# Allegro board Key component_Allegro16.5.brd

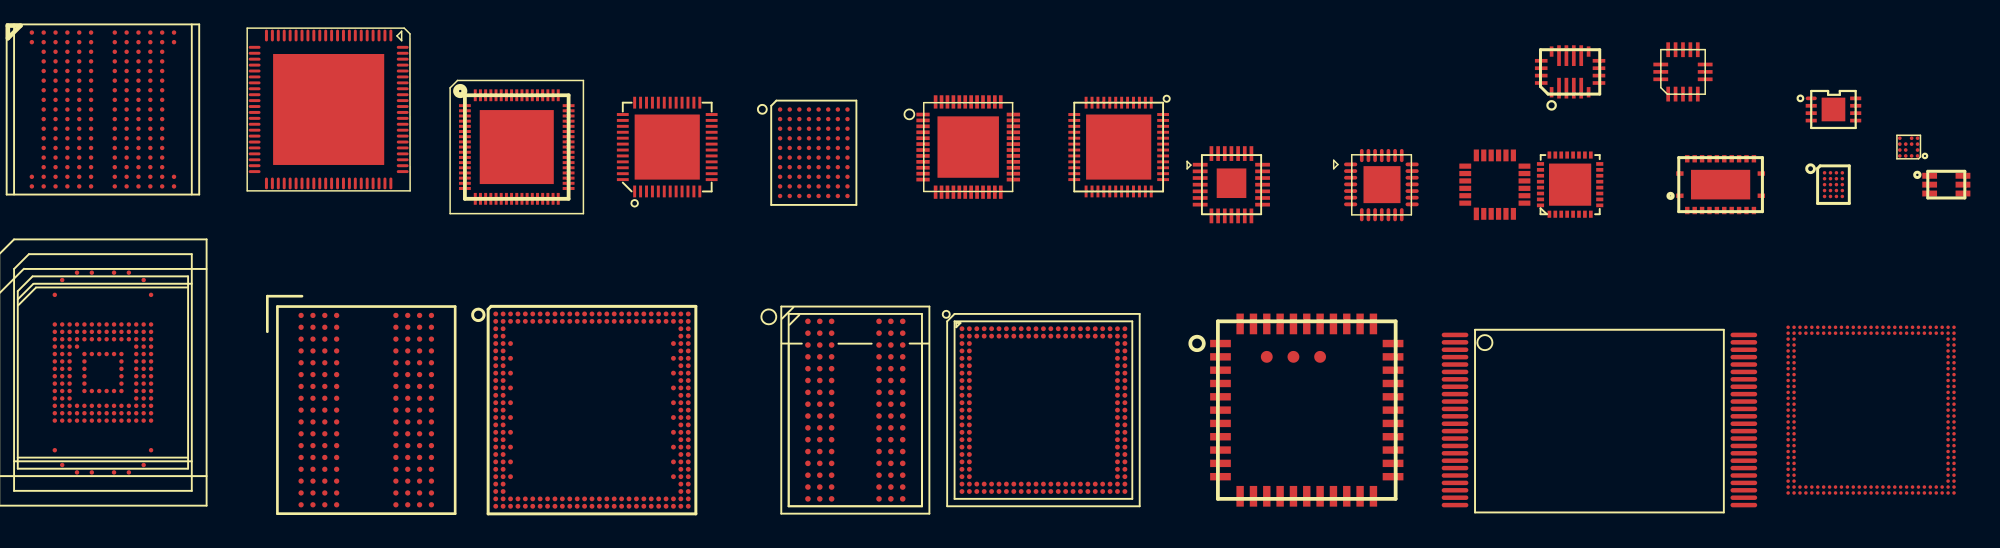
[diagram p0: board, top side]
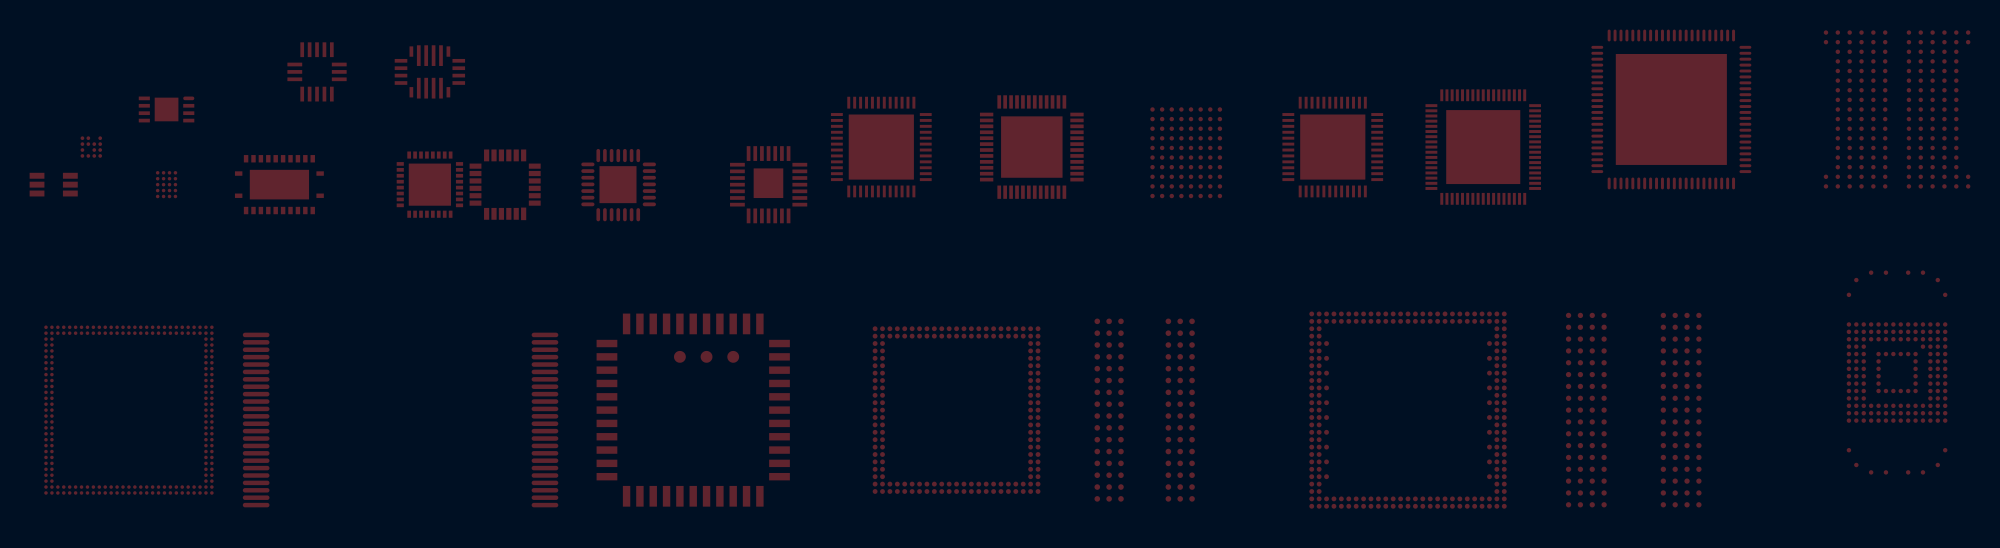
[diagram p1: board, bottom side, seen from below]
No outline. copper layers: TOP, BOTTOM. Coordinates in mm from the lowest, leftmost part position.

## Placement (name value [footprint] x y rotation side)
U1  -  [136BALL-FBGA]  17.78 0 0 top
U2  -  [763_ALC3224]  58.42 17.78 0 top
U3  -  [ALC5616_QFN32]  99.06 15.24 0 top
U4  -  [ALC5631Q]  68.58 17.78 0 top
U5  -  [AP6XXX]  81.28 0 0 top
U6  -  [BAG14-1_6X1_6]  121.92 17.78 0 top
U7  -  [CSP0608-80]  45.72 20.32 0 top
U8  -  [CW2013]  116.84 20.32 0 top
U9  -  [ES8323-]  86.36 15.24 0 top
U10  -  [B-168P_12-12]  63.5 0 0 top
U11  -  [FBGA178-13X11_5]  0 20.32 0 top
U12  -  [FBGA216-12X12]  119.38 0 0 top
U13  -  [FBGA220-14X14]  33.02 0 0 top
U14  -  [FBGA96-10X14]  50.8 0 0 top
U15  -  [INAND_169]  0 2.54 0 top
U16  -  [LGA16]  106.68 22.86 0 top
U17  -  [MPU6050C]  93.98 15.24 0 top
U18  -  [OPLGA6]  124.46 15.24 0 top
U19  -  [QFN20-3X4]  99.06 22.86 0 top
U20  -  [QFN48-6X6]  38.1 17.78 0 top
U21  -  [QFN68-7X7]  27.94 17.78 0 top
U22  -  [QFN88]  15.24 20.32 0 top
U23  -  [TSOP1-48]  91.44 5.08 0 top
U24  -  [VQFN24]  109.22 15.24 0 top
U25  -  [WLCSP-20]  116.84 15.24 0 top
U26  -  [WM8988]  76.2 15.24 0 top

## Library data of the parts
U1 = 136BALL-FBGA
U2 = 763_ALC3224
U3 = ALC5616_QFN32
U4 = ALC5631Q
U5 = AP6XXX
U6 = BAG14-1_6X1_6
U7 = CSP0608-80
U8 = CW2013
U9 = ES8323-
U10 = FBGA168-12X12
U11 = FBGA178-13X11_5
U12 = FBGA216-12X12
U13 = FBGA220-14X14
U14 = FBGA96-10X14
U15 = INAND_169
U16 = LGA16
U17 = MPU6050C
U18 = OPLGA6
U19 = QFN20-3X4
U20 = QFN48-6X6
U21 = QFN68-7X7
U22 = QFN88
U23 = TSOP1-48
U24 = VQFN24
U25 = WLCSP-20
U26 = WM8988

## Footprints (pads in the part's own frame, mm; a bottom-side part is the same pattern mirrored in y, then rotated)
136BALL-FBGA
  round 0.36 smd: A1(-4.4,6.4) A2(-3.6,6.4) A3(-2.8,6.4) A4(-2,6.4) A9(2,6.4) A10(2.8,6.4) A11(3.6,6.4) A12(4.4,6.4) B1(-4.4,5.6) B2(-3.6,5.6) B3(-2.8,5.6) B4(-2,5.6) B9(2,5.6) B10(2.8,5.6) B11(3.6,5.6) B12(4.4,5.6) C1(-4.4,4.8) C2(-3.6,4.8) C3(-2.8,4.8) C4(-2,4.8) C9(2,4.8) C10(2.8,4.8) C11(3.6,4.8) C12(4.4,4.8) D1(-4.4,4) D2(-3.6,4) D3(-2.8,4) D4(-2,4) D9(2,4) D10(2.8,4) D11(3.6,4) D12(4.4,4) E1(-4.4,3.2) E2(-3.6,3.2) E3(-2.8,3.2) E4(-2,3.2) E9(2,3.2) E10(2.8,3.2) E11(3.6,3.2) E12(4.4,3.2) F1(-4.4,2.4) F2(-3.6,2.4) F3(-2.8,2.4) F4(-2,2.4) F9(2,2.4) F10(2.8,2.4) F11(3.6,2.4) F12(4.4,2.4) G1(-4.4,1.6) G2(-3.6,1.6) G3(-2.8,1.6) G4(-2,1.6) G9(2,1.6) G10(2.8,1.6) G11(3.6,1.6) G12(4.4,1.6) H1(-4.4,0.8) H2(-3.6,0.8) H3(-2.8,0.8) H4(-2,0.8) H9(2,0.8) H10(2.8,0.8) H11(3.6,0.8) H12(4.4,0.8) J1(-4.4,0) J2(-3.6,0) J3(-2.8,0) J4(-2,0) J9(2,0) J10(2.8,0) J11(3.6,0) J12(4.4,0) K1(-4.4,-0.8) K2(-3.6,-0.8) K3(-2.8,-0.8) K4(-2,-0.8) K9(2,-0.8) K10(2.8,-0.8) K11(3.6,-0.8) K12(4.4,-0.8) L1(-4.4,-1.6) L2(-3.6,-1.6) L3(-2.8,-1.6) L4(-2,-1.6) L9(2,-1.6) L10(2.8,-1.6) L11(3.6,-1.6) L12(4.4,-1.6) M1(-4.4,-2.4) M2(-3.6,-2.4) M3(-2.8,-2.4) M4(-2,-2.4) M9(2,-2.4) M10(2.8,-2.4) M11(3.6,-2.4) M12(4.4,-2.4) N1(-4.4,-3.2) N2(-3.6,-3.2) N3(-2.8,-3.2) N4(-2,-3.2) N9(2,-3.2) N10(2.8,-3.2) N11(3.6,-3.2) N12(4.4,-3.2) P1(-4.4,-4) P2(-3.6,-4) P3(-2.8,-4) P4(-2,-4) P9(2,-4) P10(2.8,-4) P11(3.6,-4) P12(4.4,-4) R1(-4.4,-4.8) R2(-3.6,-4.8) R3(-2.8,-4.8) R4(-2,-4.8) R9(2,-4.8) R10(2.8,-4.8) R11(3.6,-4.8) R12(4.4,-4.8) T1(-4.4,-5.6) T2(-3.6,-5.6) T3(-2.8,-5.6) T4(-2,-5.6) T9(2,-5.6) T10(2.8,-5.6) T11(3.6,-5.6) T12(4.4,-5.6) U1(-4.4,-6.4) U2(-3.6,-6.4) U3(-2.8,-6.4) U4(-2,-6.4) U9(2,-6.4) U10(2.8,-6.4) U11(3.6,-6.4) U12(4.4,-6.4)
763_ALC3224
  rect 0.9x0.249 smd: 1(-3.05,2.2) 2(-3.05,1.8) 3(-3.05,1.4) 4(-3.05,1) 5(-3.05,0.6) 6(-3.05,0.2) 7(-3.05,-0.2) 8(-3.05,-0.6) 9(-3.05,-1) 10(-3.05,-1.4) 11(-3.05,-1.8) 12(-3.05,-2.2) 25(3.05,-2.2) 26(3.05,-1.8) 27(3.05,-1.4) 28(3.05,-1) 29(3.05,-0.6) 30(3.05,-0.2) 31(3.05,0.2) 32(3.05,0.6) 33(3.05,1) 34(3.05,1.4) 35(3.05,1.8) 36(3.05,2.2)
  rect 0.249x0.9 smd: 13(-2.2,-3.05) 14(-1.8,-3.05) 15(-1.4,-3.05) 16(-1,-3.05) 17(-0.6,-3.05) 18(-0.2,-3.05) 19(0.2,-3.05) 20(0.6,-3.05) 21(1,-3.05) 22(1.4,-3.05) 23(1.8,-3.05) 24(2.2,-3.05) 37(2.2,3.05) 38(1.8,3.05) 39(1.4,3.05) 40(1,3.05) 41(0.6,3.05) 42(0.2,3.05) 43(-0.2,3.05) 44(-0.6,3.05) 45(-1,3.05) 46(-1.4,3.05) 47(-1.8,3.05) 48(-2.2,3.05)
  rect 4.15x4.15 smd: 49(0,0)
ALC5616_QFN32
  rect 0.25x0.482 smd: 1(-1.4,-2) 2(-1,-2) 3(-0.6,-2) 4(-0.2,-2) 5(0.2,-2) 6(0.6,-2) 7(1,-2) 8(1.4,-2) 17(1.4,2) 18(1,2) 19(0.6,2) 20(0.2,2) 21(-0.2,2) 22(-0.6,2) 23(-1,2) 24(-1.4,2)
  rect 0.482x0.25 smd: 9(2,-1.4) 10(2,-1) 11(2,-0.6) 12(2,-0.2) 13(2,0.2) 14(2,0.6) 15(2,1) 16(2,1.4) 25(-2,1.4) 26(-2,1) 27(-2,0.6) 28(-2,0.2) 29(-2,-0.2) 30(-2,-0.6) 31(-2,-1) 32(-2,-1.4)
  rect 2.85x2.85 smd: 33(0,0)
ALC5631Q
  rect 0.2x0.8 smd: 1(2.2,3) 2(1.8,3) 3(1.4,3) 4(1,3) 5(0.6,3) 6(0.2,3) 7(-0.2,3) 8(-0.6,3) 9(-1,3) 10(-1.4,3) 11(-1.8,3) 12(-2.2,3) 25(-2.2,-3) 26(-1.8,-3) 27(-1.4,-3) 28(-1,-3) 29(-0.6,-3) 30(-0.2,-3) 31(0.2,-3) 32(0.6,-3) 33(1,-3) 34(1.4,-3) 35(1.8,-3) 36(2.2,-3)
  rect 0.8x0.2 smd: 13(-3,2.2) 14(-3,1.8) 15(-3,1.4) 16(-3,1) 17(-3,0.6) 18(-3,0.2) 19(-3,-0.2) 20(-3,-0.6) 21(-3,-1) 22(-3,-1.4) 23(-3,-1.8) 24(-3,-2.2) 37(3,-2.2) 38(3,-1.8) 39(3,-1.4) 40(3,-1) 41(3,-0.6) 42(3,-0.2) 43(3,0.2) 44(3,0.6) 45(3,1) 46(3,1.4) 47(3,1.8) 48(3,2.2)
  rect 4.4x4.4 smd: 49(0,0)
AP6XXX
  rect 1.4x0.5 smd: 1(-5.825,4.5) 2(-5.825,3.6) 3(-5.825,2.7) 4(-5.825,1.8) 5(-5.825,0.9) 6(-5.825,0) 7(-5.825,-0.9) 8(-5.825,-1.8) 9(-5.825,-2.7) 10(-5.825,-3.6) 11(-5.825,-4.5) 23(5.825,-4.5) 24(5.825,-3.6) 25(5.825,-2.7) 26(5.825,-1.8) 27(5.825,-0.9) 28(5.825,0) 29(5.825,0.9) 30(5.825,1.8) 31(5.825,2.7) 32(5.825,3.6) 33(5.825,4.5)
  rect 0.5x1.4 smd: 12(-4.5,-5.825) 13(-3.6,-5.825) 14(-2.7,-5.825) 15(-1.8,-5.825) 16(-0.9,-5.825) 17(0,-5.825) 18(0.9,-5.825) 19(1.8,-5.825) 20(2.7,-5.825) 21(3.6,-5.825) 22(4.5,-5.825) 34(4.5,5.825) 35(3.6,5.825) 36(2.7,5.825) 37(1.8,5.825) 38(0.9,5.825) 39(0,5.825) 40(-0.9,5.825) 41(-1.8,5.825) 42(-2.7,5.825) 43(-3.6,5.825) 44(-4.5,5.825)
  round 0.8 smd: 45(-2.7,3.6) 46(-0.9,3.6) 47(0.9,3.6)
B-168P_12-12
  round 0.33 smd: A1(-5.5,5.5) A2(-5,5.5) A3(-4.5,5.5) A4(-4,5.5) A5(-3.5,5.5) A6(-3,5.5) A7(-2.5,5.5) A8(-2,5.5) A9(-1.5,5.5) A10(-1,5.5) A11(-0.5,5.5) A12(0,5.5) A13(0.5,5.5) A14(1,5.5) A15(1.5,5.5) A16(2,5.5) A17(2.5,5.5) A18(3,5.5) A19(3.5,5.5) A20(4,5.5) A21(4.5,5.5) A22(5,5.5) A23(5.5,5.5) AA1(-5.5,-4.5) AA2(-5,-4.5) AA22(5,-4.5) AA23(5.5,-4.5) AB1(-5.5,-5) AB2(-5,-5) AB3(-4.5,-5) AB4(-4,-5) AB5(-3.5,-5) AB6(-3,-5) AB7(-2.5,-5) AB8(-2,-5) AB9(-1.5,-5) AB10(-1,-5) AB11(-0.5,-5) AB12(0,-5) AB13(0.5,-5) AB14(1,-5) AB15(1.5,-5) AB16(2,-5) AB17(2.5,-5) AB18(3,-5) AB19(3.5,-5) AB20(4,-5) AB21(4.5,-5) AB22(5,-5) AB23(5.5,-5) AC1(-5.5,-5.5) AC2(-5,-5.5) AC3(-4.5,-5.5) AC4(-4,-5.5) AC5(-3.5,-5.5) AC6(-3,-5.5) AC7(-2.5,-5.5) AC8(-2,-5.5) AC9(-1.5,-5.5) AC10(-1,-5.5) AC11(-0.5,-5.5) AC12(0,-5.5) AC13(0.5,-5.5) AC14(1,-5.5) AC15(1.5,-5.5) AC16(2,-5.5) AC17(2.5,-5.5) AC18(3,-5.5) AC19(3.5,-5.5) AC20(4,-5.5) AC21(4.5,-5.5) AC22(5,-5.5) AC23(5.5,-5.5) B1(-5.5,5) B2(-5,5) B3(-4.5,5) B4(-4,5) B5(-3.5,5) B6(-3,5) B7(-2.5,5) B8(-2,5) B9(-1.5,5) B10(-1,5) B11(-0.5,5) B12(0,5) B13(0.5,5) B14(1,5) B15(1.5,5) B16(2,5) B17(2.5,5) B18(3,5) B19(3.5,5) B20(4,5) B21(4.5,5) B22(5,5) B23(5.5,5) C1(-5.5,4.5) C2(-5,4.5) C22(5,4.5) C23(5.5,4.5) D1(-5.5,4) D2(-5,4) D22(5,4) D23(5.5,4) E1(-5.5,3.5) E2(-5,3.5) E22(5,3.5) E23(5.5,3.5) F1(-5.5,3) F2(-5,3) F22(5,3) F23(5.5,3) G1(-5.5,2.5) G2(-5,2.5) G22(5,2.5) G23(5.5,2.5) H1(-5.5,2) H2(-5,2) H22(5,2) H23(5.5,2) J1(-5.5,1.5) J2(-5,1.5) J22(5,1.5) J23(5.5,1.5) K1(-5.5,1) K2(-5,1) K22(5,1) K23(5.5,1) L1(-5.5,0.5) L2(-5,0.5) L22(5,0.5) L23(5.5,0.5) M1(-5.5,0) M2(-5,0) M22(5,0) M23(5.5,0) N1(-5.5,-0.5) N2(-5,-0.5) N22(5,-0.5) N23(5.5,-0.5) P1(-5.5,-1) P2(-5,-1) P22(5,-1) P23(5.5,-1) R1(-5.5,-1.5) R2(-5,-1.5) R22(5,-1.5) R23(5.5,-1.5) T1(-5.5,-2) T2(-5,-2) T22(5,-2) T23(5.5,-2) U1(-5.5,-2.5) U2(-5,-2.5) U22(5,-2.5) U23(5.5,-2.5) V1(-5.5,-3) V2(-5,-3) V22(5,-3) V23(5.5,-3) W1(-5.5,-3.5) W2(-5,-3.5) W22(5,-3.5) W23(5.5,-3.5) Y1(-5.5,-4) Y2(-5,-4) Y22(5,-4) Y23(5.5,-4)
BAG14-1_6X1_6
  round 0.25 smd: A1(0.6,-0.6) A2(0.2,-0.6) A3(-0.2,-0.6) A4(-0.6,-0.6) B1(0.6,-0.2) B3(-0.2,-0.2) B4(-0.6,-0.2) C1(0.6,0.2) C2(0.2,0.2) C3(-0.2,0.2) C4(-0.6,0.2) D1(0.6,0.6) D2(0.2,0.6) D4(-0.6,0.6)
CSP0608-80
  round 0.3 smd: A1(0,0) A2(0.65,0) A3(1.3,0) A4(1.95,0) A5(2.6,0) A6(3.25,0) A7(3.9,0) A8(4.55,0) B1(0,-0.65) B2(0.65,-0.65) B3(1.3,-0.65) B4(1.95,-0.65) B5(2.6,-0.65) B6(3.25,-0.65) B7(3.9,-0.65) B8(4.55,-0.65) C1(0,-1.3) C2(0.65,-1.3) C3(1.3,-1.3) C4(1.95,-1.3) C5(2.6,-1.3) C6(3.25,-1.3) C7(3.9,-1.3) C8(4.55,-1.3) D1(0,-1.95) D2(0.65,-1.95) D3(1.3,-1.95) D4(1.95,-1.95) D5(2.6,-1.95) D6(3.25,-1.95) D7(3.9,-1.95) D8(4.55,-1.95) E1(0,-2.6) E2(0.65,-2.6) E3(1.3,-2.6) E4(1.95,-2.6) E5(2.6,-2.6) E6(3.25,-2.6) E7(3.9,-2.6) E8(4.55,-2.6) F1(0,-3.25) F2(0.65,-3.25) F3(1.3,-3.25) F4(1.95,-3.25) F5(2.6,-3.25) F6(3.25,-3.25) F7(3.9,-3.25) F8(4.55,-3.25) G1(0,-3.9) G2(0.65,-3.9) G3(1.3,-3.9) G4(1.95,-3.9) G5(2.6,-3.9) G6(3.25,-3.9) G7(3.9,-3.9) G8(4.55,-3.9) H1(0,-4.55) H2(0.65,-4.55) H3(1.3,-4.55) H4(1.95,-4.55) H5(2.6,-4.55) H6(3.25,-4.55) H7(3.9,-4.55) H8(4.55,-4.55) J1(0,-5.2) J2(0.65,-5.2) J3(1.3,-5.2) J4(1.95,-5.2) J5(2.6,-5.2) J6(3.25,-5.2) J7(3.9,-5.2) J8(4.55,-5.2) K1(0,-5.85) K2(0.65,-5.85) K3(1.3,-5.85) K4(1.95,-5.85) K5(2.6,-5.85) K6(3.25,-5.85) K7(3.9,-5.85) K8(4.55,-5.85)
CW2013
  oval 0.75x0.25 smd: 1(-1.5,0.75)
  rect 0.75x0.25 smd: 2(-1.5,0.25) 3(-1.5,-0.25) 4(-1.5,-0.75) 5(1.5,-0.75) 6(1.5,-0.25) 7(1.5,0.25) 8(1.5,0.75)
  rect 1.6x1.6 smd: 9(0,0)
ES8323-
  oval 0.889x0.254 smd: 1(-2.118,1.367) 2(-2.118,0.917) 3(-2.118,0.467) 4(-2.118,0.017) 5(-2.118,-0.433) 6(-2.118,-0.883) 7(-2.118,-1.333) 15(2.032,-1.333) 16(2.032,-0.883) 17(2.032,-0.433) 18(2.032,0.017) 19(2.032,0.467) 20(2.032,0.917) 21(2.032,1.367)
  oval 0.245x0.889 smd: 8(-1.368,-2.033) 9(-0.918,-2.033) 10(-0.468,-2.033) 11(-0.018,-2.033) 12(0.432,-2.033) 13(0.882,-2.033) 14(1.332,-2.033) 22(1.332,1.967) 23(0.882,1.967) 24(0.432,1.967) 25(-0.018,1.967) 26(-0.468,1.967) 27(-0.918,1.967) 28(-1.368,1.967)
  rect 2.5x2.5 smd: 29(0,0)
FBGA96-10X14
  round 0.38 smd: A1(-3.2,6) A2(-2.4,6) A3(-1.6,6) A7(1.6,6) A8(2.4,6) A9(3.2,6) B1(-3.2,5.2) B2(-2.4,5.2) B3(-1.6,5.2) B7(1.6,5.2) B8(2.4,5.2) B9(3.2,5.2) C1(-3.2,4.4) C2(-2.4,4.4) C3(-1.6,4.4) C7(1.6,4.4) C8(2.4,4.4) C9(3.2,4.4) D1(-3.2,3.6) D2(-2.4,3.6) D3(-1.6,3.6) D7(1.6,3.6) D8(2.4,3.6) D9(3.2,3.6) E1(-3.2,2.8) E2(-2.4,2.8) E3(-1.6,2.8) E7(1.6,2.8) E8(2.4,2.8) E9(3.2,2.8) F1(-3.2,2) F2(-2.4,2) F3(-1.6,2) F7(1.6,2) F8(2.4,2) F9(3.2,2) G1(-3.2,1.2) G2(-2.4,1.2) G3(-1.6,1.2) G7(1.6,1.2) G8(2.4,1.2) G9(3.2,1.2) H1(-3.2,0.4) H2(-2.4,0.4) H3(-1.6,0.4) H7(1.6,0.4) H8(2.4,0.4) H9(3.2,0.4) J1(-3.2,-0.4) J2(-2.4,-0.4) J3(-1.6,-0.4) J7(1.6,-0.4) J8(2.4,-0.4) J9(3.2,-0.4) K1(-3.2,-1.2) K2(-2.4,-1.2) K3(-1.6,-1.2) K7(1.6,-1.2) K8(2.4,-1.2) K9(3.2,-1.2) L1(-3.2,-2) L2(-2.4,-2) L3(-1.6,-2) L7(1.6,-2) L8(2.4,-2) L9(3.2,-2) M1(-3.2,-2.8) M2(-2.4,-2.8) M3(-1.6,-2.8) M7(1.6,-2.8) M8(2.4,-2.8) M9(3.2,-2.8) N1(-3.2,-3.6) N2(-2.4,-3.6) N3(-1.6,-3.6) N7(1.6,-3.6) N8(2.4,-3.6) N9(3.2,-3.6) P1(-3.2,-4.4) P2(-2.4,-4.4) P3(-1.6,-4.4) P7(1.6,-4.4) P8(2.4,-4.4) P9(3.2,-4.4) R1(-3.2,-5.2) R2(-2.4,-5.2) R3(-1.6,-5.2) R7(1.6,-5.2) R8(2.4,-5.2) R9(3.2,-5.2) T1(-3.2,-6) T2(-2.4,-6) T3(-1.6,-6) T7(1.6,-6) T8(2.4,-6) T9(3.2,-6)
FBGA178-13X11_5
  round 0.3 smd: A1(-4.8,5.2) A2(-4,5.2) A3(-3.2,5.2) A4(-2.4,5.2) A5(-1.6,5.2) A6(-0.8,5.2) A8(0.8,5.2) A9(1.6,5.2) A10(2.4,5.2) A11(3.2,5.2) A12(4,5.2) A13(4.8,5.2) B1(-4.8,4.55) B2(-4,4.55) B3(-3.2,4.55) B4(-2.4,4.55) B5(-1.6,4.55) B6(-0.8,4.55) B8(0.8,4.55) B9(1.6,4.55) B10(2.4,4.55) B11(3.2,4.55) B12(4,4.55) B13(4.8,4.55) C2(-4,3.9) C3(-3.2,3.9) C4(-2.4,3.9) C5(-1.6,3.9) C6(-0.8,3.9) C8(0.8,3.9) C9(1.6,3.9) C10(2.4,3.9) C11(3.2,3.9) C12(4,3.9) D2(-4,3.25) D3(-3.2,3.25) D4(-2.4,3.25) D5(-1.6,3.25) D6(-0.8,3.25) D8(0.8,3.25) D9(1.6,3.25) D10(2.4,3.25) D11(3.2,3.25) D12(4,3.25) E2(-4,2.6) E3(-3.2,2.6) E4(-2.4,2.6) E5(-1.6,2.6) E6(-0.8,2.6) E8(0.8,2.6) E9(1.6,2.6) E10(2.4,2.6) E11(3.2,2.6) E12(4,2.6) F2(-4,1.95) F3(-3.2,1.95) F4(-2.4,1.95) F5(-1.6,1.95) F6(-0.8,1.95) F8(0.8,1.95) F9(1.6,1.95) F10(2.4,1.95) F11(3.2,1.95) F12(4,1.95) G2(-4,1.3) G3(-3.2,1.3) G4(-2.4,1.3) G5(-1.6,1.3) G6(-0.8,1.3) G8(0.8,1.3) G9(1.6,1.3) G10(2.4,1.3) G11(3.2,1.3) G12(4,1.3) H2(-4,0.65) H3(-3.2,0.65) H4(-2.4,0.65) H5(-1.6,0.65) H6(-0.8,0.65) H8(0.8,0.65) H9(1.6,0.65) H10(2.4,0.65) H11(3.2,0.65) H12(4,0.65) J2(-4,0) J3(-3.2,0) J4(-2.4,0) J5(-1.6,0) J6(-0.8,0) J8(0.8,0) J9(1.6,0) J10(2.4,0) J11(3.2,0) J12(4,0) K2(-4,-0.65) K3(-3.2,-0.65) K4(-2.4,-0.65) K5(-1.6,-0.65) K6(-0.8,-0.65) K8(0.8,-0.65) K9(1.6,-0.65) K10(2.4,-0.65) K11(3.2,-0.65) K12(4,-0.65) L2(-4,-1.3) L3(-3.2,-1.3) L4(-2.4,-1.3) L5(-1.6,-1.3) L6(-0.8,-1.3) L8(0.8,-1.3) L9(1.6,-1.3) L10(2.4,-1.3) L11(3.2,-1.3) L12(4,-1.3) M2(-4,-1.95) M3(-3.2,-1.95) M4(-2.4,-1.95) M5(-1.6,-1.95) M6(-0.8,-1.95) M8(0.8,-1.95) M9(1.6,-1.95) M10(2.4,-1.95) M11(3.2,-1.95) M12(4,-1.95) N2(-4,-2.6) N3(-3.2,-2.6) N4(-2.4,-2.6) N5(-1.6,-2.6) N6(-0.8,-2.6) N8(0.8,-2.6) N9(1.6,-2.6) N10(2.4,-2.6) N11(3.2,-2.6) N12(4,-2.6) P2(-4,-3.25) P3(-3.2,-3.25) P4(-2.4,-3.25) P5(-1.6,-3.25) P6(-0.8,-3.25) P8(0.8,-3.25) P9(1.6,-3.25) P10(2.4,-3.25) P11(3.2,-3.25) P12(4,-3.25) R2(-4,-3.9) R3(-3.2,-3.9) R4(-2.4,-3.9) R5(-1.6,-3.9) R6(-0.8,-3.9) R8(0.8,-3.9) R9(1.6,-3.9) R10(2.4,-3.9) R11(3.2,-3.9) R12(4,-3.9) T1(-4.8,-4.55) T2(-4,-4.55) T3(-3.2,-4.55) T4(-2.4,-4.55) T5(-1.6,-4.55) T6(-0.8,-4.55) T8(0.8,-4.55) T9(1.6,-4.55) T10(2.4,-4.55) T11(3.2,-4.55) T12(4,-4.55) T13(4.8,-4.55) U1(-4.8,-5.2) U2(-4,-5.2) U3(-3.2,-5.2) U4(-2.4,-5.2) U5(-1.6,-5.2) U6(-0.8,-5.2) U8(0.8,-5.2) U9(1.6,-5.2) U10(2.4,-5.2) U11(3.2,-5.2) U12(4,-5.2) U13(4.8,-5.2)
FBGA216-12X12
  round 0.24 smd: A1(-5.6,5.6) A2(-5.2,5.6) A3(-4.8,5.6) A4(-4.4,5.6) A5(-4,5.6) A6(-3.6,5.6) A7(-3.2,5.6) A8(-2.8,5.6) A9(-2.4,5.6) A10(-2,5.6) A11(-1.6,5.6) A12(-1.2,5.6) A13(-0.8,5.6) A14(-0.4,5.6) A15(0,5.6) A16(0.4,5.6) A17(0.8,5.6) A18(1.2,5.6) A19(1.6,5.6) A20(2,5.6) A21(2.4,5.6) A22(2.8,5.6) A23(3.2,5.6) A24(3.6,5.6) A25(4,5.6) A26(4.4,5.6) A27(4.8,5.6) A28(5.2,5.6) A29(5.6,5.6) AA1(-5.6,-2.4) AA2(-5.2,-2.4) AA28(5.2,-2.4) AA29(5.6,-2.4) AB1(-5.6,-2.8) AB2(-5.2,-2.8) AB28(5.2,-2.8) AB29(5.6,-2.8) AC1(-5.6,-3.2) AC2(-5.2,-3.2) AC28(5.2,-3.2) AC29(5.6,-3.2) AD1(-5.6,-3.6) AD2(-5.2,-3.6) AD28(5.2,-3.6) AD29(5.6,-3.6) AE1(-5.6,-4) AE2(-5.2,-4) AE28(5.2,-4) AE29(5.6,-4) AF1(-5.6,-4.4) AF2(-5.2,-4.4) AF28(5.2,-4.4) AF29(5.6,-4.4) AG1(-5.6,-4.8) AG2(-5.2,-4.8) AG28(5.2,-4.8) AG29(5.6,-4.8) AH1(-5.6,-5.2) AH2(-5.2,-5.2) AH3(-4.8,-5.2) AH4(-4.4,-5.2) AH5(-4,-5.2) AH6(-3.6,-5.2) AH7(-3.2,-5.2) AH8(-2.8,-5.2) AH9(-2.4,-5.2) AH10(-2,-5.2) AH11(-1.6,-5.2) AH12(-1.2,-5.2) AH13(-0.8,-5.2) AH14(-0.4,-5.2) AH15(0,-5.2) AH16(0.4,-5.2) AH17(0.8,-5.2) AH18(1.2,-5.2) AH19(1.6,-5.2) AH20(2,-5.2) AH21(2.4,-5.2) AH22(2.8,-5.2) AH23(3.2,-5.2) AH24(3.6,-5.2) AH25(4,-5.2) AH26(4.4,-5.2) AH27(4.8,-5.2) AH28(5.2,-5.2) AH29(5.6,-5.2) AJ1(-5.6,-5.6) AJ2(-5.2,-5.6) AJ3(-4.8,-5.6) AJ4(-4.4,-5.6) AJ5(-4,-5.6) AJ6(-3.6,-5.6) AJ7(-3.2,-5.6) AJ8(-2.8,-5.6) AJ9(-2.4,-5.6) AJ10(-2,-5.6) AJ11(-1.6,-5.6) AJ12(-1.2,-5.6) AJ13(-0.8,-5.6) AJ14(-0.4,-5.6) AJ15(0,-5.6) AJ16(0.4,-5.6) AJ17(0.8,-5.6) AJ18(1.2,-5.6) AJ19(1.6,-5.6) AJ20(2,-5.6) AJ21(2.4,-5.6) AJ22(2.8,-5.6) AJ23(3.2,-5.6) AJ24(3.6,-5.6) AJ25(4,-5.6) AJ26(4.4,-5.6) AJ27(4.8,-5.6) AJ28(5.2,-5.6) AJ29(5.6,-5.6) B1(-5.6,5.2) B2(-5.2,5.2) B3(-4.8,5.2) B4(-4.4,5.2) B5(-4,5.2) B6(-3.6,5.2) B7(-3.2,5.2) B8(-2.8,5.2) B9(-2.4,5.2) B10(-2,5.2) B11(-1.6,5.2) B12(-1.2,5.2) B13(-0.8,5.2) B14(-0.4,5.2) B15(0,5.2) B16(0.4,5.2) B17(0.8,5.2) B18(1.2,5.2) B19(1.6,5.2) B20(2,5.2) B21(2.4,5.2) B22(2.8,5.2) B23(3.2,5.2) B24(3.6,5.2) B25(4,5.2) B26(4.4,5.2) B27(4.8,5.2) B28(5.2,5.2) B29(5.6,5.2) C1(-5.6,4.8) C2(-5.2,4.8) C28(5.2,4.8) C29(5.6,4.8) D1(-5.6,4.4) D2(-5.2,4.4) D28(5.2,4.4) D29(5.6,4.4) E1(-5.6,4) E2(-5.2,4) E28(5.2,4) E29(5.6,4) F1(-5.6,3.6) F2(-5.2,3.6) F28(5.2,3.6) F29(5.6,3.6) G1(-5.6,3.2) G2(-5.2,3.2) G28(5.2,3.2) G29(5.6,3.2) H1(-5.6,2.8) H2(-5.2,2.8) H28(5.2,2.8) H29(5.6,2.8) J1(-5.6,2.4) J2(-5.2,2.4) J28(5.2,2.4) J29(5.6,2.4) K1(-5.6,2) K2(-5.2,2) K28(5.2,2) K29(5.6,2) L1(-5.6,1.6) L2(-5.2,1.6) L28(5.2,1.6) L29(5.6,1.6) M1(-5.6,1.2) M2(-5.2,1.2) M28(5.2,1.2) M29(5.6,1.2) N1(-5.6,0.8) N2(-5.2,0.8) N28(5.2,0.8) N29(5.6,0.8) P1(-5.6,0.4) P2(-5.2,0.4) P28(5.2,0.4) P29(5.6,0.4) R1(-5.6,0) R2(-5.2,0) R28(5.2,0) R29(5.6,0) T1(-5.6,-0.4) T2(-5.2,-0.4) T28(5.2,-0.4) T29(5.6,-0.4) U1(-5.6,-0.8) U2(-5.2,-0.8) U28(5.2,-0.8) U29(5.6,-0.8) V1(-5.6,-1.2) V2(-5.2,-1.2) V28(5.2,-1.2) V29(5.6,-1.2) W1(-5.6,-1.6) W2(-5.2,-1.6) W28(5.2,-1.6) W29(5.6,-1.6) Y1(-5.6,-2) Y2(-5.2,-2) Y28(5.2,-2) Y29(5.6,-2)
FBGA220-14X14
  round 0.33 smd: A1(-6.5,6.5) A2(-6,6.5) A3(-5.5,6.5) A4(-5,6.5) A5(-4.5,6.5) A6(-4,6.5) A7(-3.5,6.5) A8(-3,6.5) A9(-2.5,6.5) A10(-2,6.5) A11(-1.5,6.5) A12(-1,6.5) A13(-0.5,6.5) A14(0,6.5) A15(0.5,6.5) A16(1,6.5) A17(1.5,6.5) A18(2,6.5) A19(2.5,6.5) A20(3,6.5) A21(3.5,6.5) A22(4,6.5) A23(4.5,6.5) A24(5,6.5) A25(5.5,6.5) A26(6,6.5) A27(6.5,6.5) AA1(-6.5,-3.5) AA2(-6,-3.5) AA3(-5.5,-3.5) AA25(5.5,-3.5) AA26(6,-3.5) AA27(6.5,-3.5) AB1(-6.5,-4) AB2(-6,-4) AB26(6,-4) AB27(6.5,-4) AC1(-6.5,-4.5) AC2(-6,-4.5) AC3(-5.5,-4.5) AC25(5.5,-4.5) AC26(6,-4.5) AC27(6.5,-4.5) AD1(-6.5,-5) AD2(-6,-5) AD26(6,-5) AD27(6.5,-5) AE1(-6.5,-5.5) AE2(-6,-5.5) AE26(6,-5.5) AE27(6.5,-5.5) AF1(-6.5,-6) AF2(-6,-6) AF3(-5.5,-6) AF4(-5,-6) AF5(-4.5,-6) AF6(-4,-6) AF7(-3.5,-6) AF8(-3,-6) AF9(-2.5,-6) AF10(-2,-6) AF11(-1.5,-6) AF12(-1,-6) AF13(-0.5,-6) AF14(0,-6) AF15(0.5,-6) AF16(1,-6) AF17(1.5,-6) AF18(2,-6) AF19(2.5,-6) AF20(3,-6) AF21(3.5,-6) AF22(4,-6) AF23(4.5,-6) AF24(5,-6) AF25(5.5,-6) AF26(6,-6) AF27(6.5,-6) AG1(-6.5,-6.5) AG2(-6,-6.5) AG3(-5.5,-6.5) AG4(-5,-6.5) AG5(-4.5,-6.5) AG6(-4,-6.5) AG7(-3.5,-6.5) AG8(-3,-6.5) AG9(-2.5,-6.5) AG10(-2,-6.5) AG11(-1.5,-6.5) AG12(-1,-6.5) AG13(-0.5,-6.5) AG14(0,-6.5) AG15(0.5,-6.5) AG16(1,-6.5) AG17(1.5,-6.5) AG18(2,-6.5) AG19(2.5,-6.5) AG20(3,-6.5) AG21(3.5,-6.5) AG22(4,-6.5) AG23(4.5,-6.5) AG24(5,-6.5) AG25(5.5,-6.5) AG26(6,-6.5) AG27(6.5,-6.5) B1(-6.5,6) B2(-6,6) B3(-5.5,6) B4(-5,6) B5(-4.5,6) B6(-4,6) B7(-3.5,6) B8(-3,6) B9(-2.5,6) B10(-2,6) B11(-1.5,6) B12(-1,6) B13(-0.5,6) B14(0,6) B15(0.5,6) B16(1,6) B17(1.5,6) B18(2,6) B19(2.5,6) B20(3,6) B21(3.5,6) B22(4,6) B23(4.5,6) B24(5,6) B25(5.5,6) B26(6,6) B27(6.5,6) C1(-6.5,5.5) C2(-6,5.5) C26(6,5.5) C27(6.5,5.5) D1(-6.5,5) D2(-6,5) D26(6,5) D27(6.5,5) E1(-6.5,4.5) E2(-6,4.5) E3(-5.5,4.5) E25(5.5,4.5) E26(6,4.5) E27(6.5,4.5) F1(-6.5,4) F2(-6,4) F26(6,4) F27(6.5,4) G1(-6.5,3.5) G2(-6,3.5) G3(-5.5,3.5) G25(5.5,3.5) G26(6,3.5) G27(6.5,3.5) H1(-6.5,3) H2(-6,3) H26(6,3) H27(6.5,3) J1(-6.5,2.5) J2(-6,2.5) J3(-5.5,2.5) J25(5.5,2.5) J26(6,2.5) J27(6.5,2.5) K1(-6.5,2) K2(-6,2) K26(6,2) K27(6.5,2) L1(-6.5,1.5) L2(-6,1.5) L3(-5.5,1.5) L25(5.5,1.5) L26(6,1.5) L27(6.5,1.5) M1(-6.5,1) M2(-6,1) M26(6,1) M27(6.5,1) N1(-6.5,0.5) N2(-6,0.5) N3(-5.5,0.5) N25(5.5,0.5) N26(6,0.5) N27(6.5,0.5) P1(-6.5,0) P2(-6,0) P26(6,0) P27(6.5,0) R1(-6.5,-0.5) R2(-6,-0.5) R3(-5.5,-0.5) R25(5.5,-0.5) R26(6,-0.5) R27(6.5,-0.5) T1(-6.5,-1) T2(-6,-1) T26(6,-1) T27(6.5,-1) U1(-6.5,-1.5) U2(-6,-1.5) U3(-5.5,-1.5) U25(5.5,-1.5) U26(6,-1.5) U27(6.5,-1.5) V1(-6.5,-2) V2(-6,-2) V26(6,-2) V27(6.5,-2) W1(-6.5,-2.5) W2(-6,-2.5) W3(-5.5,-2.5) W25(5.5,-2.5) W26(6,-2.5) W27(6.5,-2.5) Y1(-6.5,-3) Y2(-6,-3) Y26(6,-3) Y27(6.5,-3)
INAND_169
  round 0.3 smd: A4(-1.75,6.75) A6(-0.75,6.75) A9(0.75,6.75) A11(1.75,6.75) AA1(-3.25,-3.25) AA2(-2.75,-3.25) AA3(-2.25,-3.25) AA4(-1.75,-3.25) AA5(-1.25,-3.25) AA6(-0.75,-3.25) AA7(-0.25,-3.25) AA8(0.25,-3.25) AA9(0.75,-3.25) AA10(1.25,-3.25) AA11(1.75,-3.25) AA12(2.25,-3.25) AA13(2.75,-3.25) AA14(3.25,-3.25) AE1(-3.25,-5.25) AE14(3.25,-5.25) AG2(-2.75,-6.25) AG13(2.75,-6.25) AH4(-1.75,-6.75) AH6(-0.75,-6.75) AH9(0.75,-6.75) AH11(1.75,-6.75) B2(-2.75,6.25) B13(2.75,6.25) D1(-3.25,5.25) D14(3.25,5.25) H1(-3.25,3.25) H2(-2.75,3.25) H3(-2.25,3.25) H4(-1.75,3.25) H5(-1.25,3.25) H6(-0.75,3.25) H7(-0.25,3.25) H8(0.25,3.25) H9(0.75,3.25) H10(1.25,3.25) H11(1.75,3.25) H12(2.25,3.25) H13(2.75,3.25) H14(3.25,3.25) J1(-3.25,2.75) J2(-2.75,2.75) J3(-2.25,2.75) J4(-1.75,2.75) J5(-1.25,2.75) J6(-0.75,2.75) J7(-0.25,2.75) J8(0.25,2.75) J9(0.75,2.75) J10(1.25,2.75) J11(1.75,2.75) J12(2.25,2.75) J13(2.75,2.75) J14(3.25,2.75) K1(-3.25,2.25) K2(-2.75,2.25) K3(-2.25,2.25) K4(-1.75,2.25) K5(-1.25,2.25) K6(-0.75,2.25) K7(-0.25,2.25) K8(0.25,2.25) K9(0.75,2.25) K10(1.25,2.25) K11(1.75,2.25) K12(2.25,2.25) K13(2.75,2.25) K14(3.25,2.25) L1(-3.25,1.75) L2(-2.75,1.75) L3(-2.25,1.75) L4(-1.75,1.75) L12(2.25,1.75) L13(2.75,1.75) L14(3.25,1.75) M1(-3.25,1.25) M2(-2.75,1.25) M3(-2.25,1.25) M5(-1.25,1.25) M6(-0.75,1.25) M7(-0.25,1.25) M8(0.25,1.25) M9(0.75,1.25) M10(1.25,1.25) M12(2.25,1.25) M13(2.75,1.25) M14(3.25,1.25) N1(-3.25,0.75) N2(-2.75,0.75) N3(-2.25,0.75) N5(-1.25,0.75) N10(1.25,0.75) N12(2.25,0.75) N13(2.75,0.75) N14(3.25,0.75) P1(-3.25,0.25) P2(-2.75,0.25) P3(-2.25,0.25) P5(-1.25,0.25) P10(1.25,0.25) P12(2.25,0.25) P13(2.75,0.25) P14(3.25,0.25) R1(-3.25,-0.25) R2(-2.75,-0.25) R3(-2.25,-0.25) R5(-1.25,-0.25) R10(1.25,-0.25) R12(2.25,-0.25) R13(2.75,-0.25) R14(3.25,-0.25) T1(-3.25,-0.75) T2(-2.75,-0.75) T3(-2.25,-0.75) T5(-1.25,-0.75) T10(1.25,-0.75) T12(2.25,-0.75) T13(2.75,-0.75) T14(3.25,-0.75) U1(-3.25,-1.25) U2(-2.75,-1.25) U3(-2.25,-1.25) U5(-1.25,-1.25) U6(-0.75,-1.25) U7(-0.25,-1.25) U8(0.25,-1.25) U9(0.75,-1.25) U10(1.25,-1.25) U12(2.25,-1.25) U13(2.75,-1.25) U14(3.25,-1.25) V1(-3.25,-1.75) V2(-2.75,-1.75) V3(-2.25,-1.75) V12(2.25,-1.75) V13(2.75,-1.75) V14(3.25,-1.75) W1(-3.25,-2.25) W2(-2.75,-2.25) W3(-2.25,-2.25) W4(-1.75,-2.25) W5(-1.25,-2.25) W6(-0.75,-2.25) W7(-0.25,-2.25) W8(0.25,-2.25) W9(0.75,-2.25) W10(1.25,-2.25) W11(1.75,-2.25) W12(2.25,-2.25) W13(2.75,-2.25) W14(3.25,-2.25) Y1(-3.25,-2.75) Y2(-2.75,-2.75) Y3(-2.25,-2.75) Y4(-1.75,-2.75) Y5(-1.25,-2.75) Y6(-0.75,-2.75) Y7(-0.25,-2.75) Y8(0.25,-2.75) Y9(0.75,-2.75) Y10(1.25,-2.75) Y11(1.75,-2.75) Y12(2.25,-2.75) Y13(2.75,-2.75) Y14(3.25,-2.75)
LGA16
  rect 0.25x1 smd: 1(-1,-1.5) 2(-0.5,-1.5) 3(0,-1.5) 4(0.5,-1.5) 5(1,-1.5) 9(1,1.5) 10(0.5,1.5) 11(0,1.5) 12(-0.5,1.5) 13(-1,1.5)
  rect 1x0.25 smd: 6(1.5,-0.5) 7(1.5,0) 8(1.5,0.5) 14(-1.5,0.5) 15(-1.5,0) 16(-1.5,-0.5)
MPU6050C
  rect 0.8x0.35 smd: 1(-2,1.25) 2(-2,0.75) 3(-2,0.25) 4(-2,-0.25) 5(-2,-0.75) 6(-2,-1.25) 13(2,-1.25) 14(2,-0.75) 15(2,-0.25) 16(2,0.25) 17(2,0.75) 18(2,1.25)
  rect 0.35x0.85 smd: 7(-1.25,-1.975)
  rect 0.35x0.8 smd: 8(-0.75,-1.975) 9(-0.25,-1.975) 10(0.25,-1.975) 11(0.75,-1.975) 12(1.25,-1.975) 19(1.25,1.975) 20(0.75,1.975) 21(0.25,1.975) 22(-0.25,1.975) 23(-0.75,1.975) 24(-1.25,1.975)
OPLGA6
  rect 1x0.4 smd: 1(-1.125,0.6) 2(-1.125,0) 3(-1.125,-0.6) 4(1.125,-0.6) 5(1.125,0) 6(1.125,0.6)
QFN20-3X4
  rect 0.25x0.7 smd: 1(-1.25,-1.375) 6(1.25,-1.375) 11(1.25,1.375) 16(-1.25,1.375)
  rect 0.25x1.4 smd: 2(-0.75,-1.1) 3(-0.25,-1.1) 4(0.25,-1.1) 5(0.75,-1.1) 12(0.75,1.1) 13(0.25,1.1) 14(-0.25,1.1) 15(-0.75,1.1)
  rect 0.85x0.25 smd: 7(1.95,-0.75) 8(1.95,-0.25) 9(1.95,0.25) 10(1.95,0.75) 17(-1.95,0.75) 18(-1.95,0.25) 19(-1.95,-0.25) 20(-1.95,-0.75)
QFN48-6X6
  rect 0.2x0.8 smd: 1(-2.2,-3) 2(-1.8,-3) 3(-1.4,-3) 4(-1,-3) 5(-0.6,-3) 6(-0.2,-3) 7(0.2,-3) 8(0.6,-3) 9(1,-3) 10(1.4,-3) 11(1.8,-3) 12(2.2,-3) 25(2.2,3) 26(1.8,3) 27(1.4,3) 28(1,3) 29(0.6,3) 30(0.2,3) 31(-0.2,3) 32(-0.6,3) 33(-1,3) 34(-1.4,3) 35(-1.8,3) 36(-2.2,3)
  rect 0.8x0.2 smd: 13(3,-2.2) 14(3,-1.8) 15(3,-1.4) 16(3,-1) 17(3,-0.6) 18(3,-0.2) 19(3,0.2) 20(3,0.6) 21(3,1) 22(3,1.4) 23(3,1.8) 24(3,2.2) 37(-3,2.2) 38(-3,1.8) 39(-3,1.4) 40(-3,1) 41(-3,0.6) 42(-3,0.2) 43(-3,-0.2) 44(-3,-0.6) 45(-3,-1) 46(-3,-1.4) 47(-3,-1.8) 48(-3,-2.2)
  rect 4.4x4.4 smd: 49(0,0)
QFN68-7X7
  rect 0.8x0.2 smd: 1(-3.5,2.8) 2(-3.5,2.45) 3(-3.5,2.1) 4(-3.5,1.75) 5(-3.5,1.4) 6(-3.5,1.05) 7(-3.5,0.7) 8(-3.5,0.35) 9(-3.5,0) 10(-3.5,-0.35) 11(-3.5,-0.7) 12(-3.5,-1.05) 13(-3.5,-1.4) 14(-3.5,-1.75) 15(-3.5,-2.1) 16(-3.5,-2.45) 17(-3.5,-2.8) 35(3.5,-2.8) 36(3.5,-2.45) 37(3.5,-2.1) 38(3.5,-1.75) 39(3.5,-1.4) 40(3.5,-1.05) 41(3.5,-0.7) 42(3.5,-0.35) 43(3.5,0) 44(3.5,0.35) 45(3.5,0.7) 46(3.5,1.05) 47(3.5,1.4) 48(3.5,1.75) 49(3.5,2.1) 50(3.5,2.45) 51(3.5,2.8)
  rect 0.2x0.8 smd: 18(-2.8,-3.5) 19(-2.45,-3.5) 20(-2.1,-3.5) 21(-1.75,-3.5) 22(-1.4,-3.5) 23(-1.05,-3.5) 24(-0.7,-3.5) 25(-0.35,-3.5) 26(0,-3.5) 27(0.35,-3.5) 28(0.7,-3.5) 29(1.05,-3.5) 30(1.4,-3.5) 31(1.75,-3.5) 32(2.1,-3.5) 33(2.45,-3.5) 34(2.8,-3.5) 52(2.8,3.5) 53(2.45,3.5) 54(2.1,3.5) 55(1.75,3.5) 56(1.4,3.5) 57(1.05,3.5) 58(0.7,3.5) 59(0.35,3.5) 60(0,3.5) 61(-0.35,3.5) 62(-0.7,3.5) 63(-1.05,3.5) 64(-1.4,3.5) 65(-1.75,3.5) 66(-2.1,3.5) 67(-2.45,3.5) 68(-2.8,3.5)
  rect 5x5 smd: 69(0,0)
QFN88
  oval 0.2x0.8 smd: 1(4.2,5) 2(3.8,5) 3(3.4,5) 4(3,5) 5(2.6,5) 6(2.2,5) 7(1.8,5) 8(1.4,5) 9(1,5) 10(0.6,5) 11(0.2,5) 12(-0.2,5) 13(-0.6,5) 14(-1,5) 15(-1.4,5) 16(-1.8,5) 17(-2.2,5) 18(-2.6,5) 19(-3,5) 20(-3.4,5) 21(-3.8,5) 22(-4.2,5) 45(-4.2,-5) 46(-3.8,-5) 47(-3.4,-5) 48(-3,-5) 49(-2.6,-5) 50(-2.2,-5) 51(-1.8,-5) 52(-1.4,-5) 53(-1,-5) 54(-0.6,-5) 55(-0.2,-5) 56(0.2,-5) 57(0.6,-5) 58(1,-5) 59(1.4,-5) 60(1.8,-5) 61(2.2,-5) 62(2.6,-5) 63(3,-5) 64(3.4,-5) 65(3.8,-5) 66(4.2,-5)
  oval 0.8x0.2 smd: 23(-5,4.2) 24(-5,3.8) 25(-5,3.4) 26(-5,3) 27(-5,2.6) 28(-5,2.2) 29(-5,1.8) 30(-5,1.4) 31(-5,1) 32(-5,0.6) 33(-5,0.2) 34(-5,-0.2) 35(-5,-0.6) 36(-5,-1) 37(-5,-1.4) 38(-5,-1.8) 39(-5,-2.2) 40(-5,-2.6) 41(-5,-3) 42(-5,-3.4) 43(-5,-3.8) 44(-5,-4.2) 67(5,-4.2) 68(5,-3.8) 69(5,-3.4) 70(5,-3) 71(5,-2.6) 72(5,-2.2) 73(5,-1.8) 74(5,-1.4) 75(5,-1) 76(5,-0.6) 77(5,-0.2) 78(5,0.2) 79(5,0.6) 80(5,1) 81(5,1.4) 82(5,1.8) 83(5,2.2) 84(5,2.6) 85(5,3) 86(5,3.4) 87(5,3.8) 88(5,4.2)
  rect 7.5x7.5 smd: 89(0,0)
TSOP1-48
  oval 1.8x0.305 smd: 1(-0.15,0) 2(-0.15,-0.5) 3(-0.15,-1) 4(-0.15,-1.5) 5(-0.15,-2) 6(-0.15,-2.5) 7(-0.15,-3) 8(-0.15,-3.5) 9(-0.15,-4) 10(-0.15,-4.5) 11(-0.15,-5) 12(-0.15,-5.5) 13(-0.15,-6) 14(-0.15,-6.5) 15(-0.15,-7) 16(-0.15,-7.5) 17(-0.15,-8) 18(-0.15,-8.5) 19(-0.15,-9) 20(-0.15,-9.5) 21(-0.15,-10) 22(-0.15,-10.5) 23(-0.15,-11) 24(-0.15,-11.5) 25(19.35,-11.5) 26(19.35,-11) 27(19.35,-10.5) 28(19.35,-10) 29(19.35,-9.5) 30(19.35,-9) 31(19.35,-8.5) 32(19.35,-8) 33(19.35,-7.5) 34(19.35,-7) 35(19.35,-6.5) 36(19.35,-6) 37(19.35,-5.5) 38(19.35,-5) 39(19.35,-4.5) 40(19.35,-4) 41(19.35,-3.5) 42(19.35,-3) 43(19.35,-2.5) 44(19.35,-2) 45(19.35,-1.5) 46(19.35,-1) 47(19.35,-0.5) 48(19.35,0)
VQFN24
  rect 0.5x0.3 smd: 1(-2.75,-0.75) 12(2.75,-0.75) 13(2.75,0.75) 24(-2.75,0.75)
  rect 0.3x0.5 smd: 2(-2.25,-1.75) 3(-1.75,-1.75) 4(-1.25,-1.75) 5(-0.75,-1.75) 6(-0.25,-1.75) 7(0.25,-1.75) 8(0.75,-1.75) 9(1.25,-1.75) 10(1.75,-1.75) 11(2.25,-1.75) 14(2.25,1.75) 15(1.75,1.75) 16(1.25,1.75) 17(0.75,1.75) 18(0.25,1.75) 19(-0.25,1.75) 20(-0.75,1.75) 21(-1.25,1.75) 22(-1.75,1.75) 23(-2.25,1.75)
  rect 4x2 smd: 25(0,0)
WLCSP-20
  round 0.24 smd: A1(-0.6,0.8) A2(-0.2,0.8) A3(0.2,0.8) A4(0.6,0.8) B1(-0.6,0.4) B2(-0.2,0.4) B3(0.2,0.4) B4(0.6,0.4) C1(-0.6,0) C2(-0.2,0) C3(0.2,0) C4(0.6,0) D1(-0.6,-0.4) D2(-0.2,-0.4) D3(0.2,-0.4) D4(0.6,-0.4) E1(-0.6,-0.8) E2(-0.2,-0.8) E3(0.2,-0.8) E4(0.6,-0.8)
WM8988
  rect 1x0.25 smd: 1(-2.117,1.348) 2(-2.117,0.898) 3(-2.117,0.448) 4(-2.117,-0.002) 5(-2.117,-0.452) 6(-2.117,-0.902) 7(-2.117,-1.352) 15(2.096,-1.352) 16(2.096,-0.902) 17(2.096,-0.452) 18(2.096,-0.002) 19(2.096,0.448) 20(2.096,0.898) 21(2.096,1.348)
  rect 0.25x1 smd: 8(-1.357,-2.113) 9(-0.907,-2.113) 10(-0.457,-2.113) 11(-0.007,-2.113) 12(0.443,-2.113) 13(0.893,-2.113) 14(1.343,-2.113) 22(1.343,2.101) 23(0.893,2.101) 24(0.443,2.101) 25(-0.007,2.101) 26(-0.457,2.101) 27(-0.907,2.101) 28(-1.357,2.101)
  rect 2x2 smd: 29(0,0.096)

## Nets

Pads without a net: U1 A1 A2 A3 A4 A9 A10 A11 A12 B1 B2 B3 B4 B9 B10 B11 B12 C1 C2 C3 C4 C9 C10 C11 C12 D1 D2 D3 D4 D9 D10 D11 D12 E1 E2 E3 E4 E9 E10 E11 E12 F1 F2 F3 F4 F9 F10 F11 F12 G1 G2 G3 G4 G9 G10 G11 G12 H1 H2 H3 H4 H9 H10 H11 H12 J1 J2 J3 J4 J9 J10 J11 J12 K1 K2 K3 K4 K9 K10 K11 K12 L1 L2 L3 L4 L9 L10 L11 L12 M1 M2 M3 M4 M9 M10 M11 M12 N1 N2 N3 N4 N9 N10 N11 N12 P1 P2 P3 P4 P9 P10 P11 P12 R1 R2 R3 R4 R9 R10 R11 R12 T1 T2 T3 T4 T9 T10 T11 T12 U1 U2 U3 U4 U9 U10 U11 U12; U2 1 2 3 4 5 6 7 8 9 10 11 12 13 14 15 16 17 18 19 20 21 22 23 24 25 26 27 28 29 30 31 32 33 34 35 36 37 38 39 40 41 42 43 44 45 46 47 48 49; U3 1 2 3 4 5 6 7 8 9 10 11 12 13 14 15 16 17 18 19 20 21 22 23 24 25 26 27 28 29 30 31 32 33; U4 1 2 3 4 5 6 7 8 9 10 11 12 13 14 15 16 17 18 19 20 21 22 23 24 25 26 27 28 29 30 31 32 33 34 35 36 37 38 39 40 41 42 43 44 45 46 47 48 49; U5 1 2 3 4 5 6 7 8 9 10 11 12 13 14 15 16 17 18 19 20 21 22 23 24 25 26 27 28 29 30 31 32 33 34 35 36 37 38 39 40 41 42 43 44 45 46 47; U6 A1 A2 A3 A4 B1 B3 B4 C1 C2 C3 C4 D1 D2 D4; U7 A1 A2 A3 A4 A5 A6 A7 A8 B1 B2 B3 B4 B5 B6 B7 B8 C1 C2 C3 C4 C5 C6 C7 C8 D1 D2 D3 D4 D5 D6 D7 D8 E1 E2 E3 E4 E5 E6 E7 E8 F1 F2 F3 F4 F5 F6 F7 F8 G1 G2 G3 G4 G5 G6 G7 G8 H1 H2 H3 H4 H5 H6 H7 H8 J1 J2 J3 J4 J5 J6 J7 J8 K1 K2 K3 K4 K5 K6 K7 K8; U8 1 2 3 4 5 6 7 8 9; U9 1 2 3 4 5 6 7 8 9 10 11 12 13 14 15 16 17 18 19 20 21 22 23 24 25 26 27 28 29; U10 A1 A2 A3 A4 A5 A6 A7 A8 A9 A10 A11 A12 A13 A14 A15 A16 A17 A18 A19 A20 A21 A22 A23 AA1 AA2 AA22 AA23 AB1 AB2 AB3 AB4 AB5 AB6 AB7 AB8 AB9 AB10 AB11 AB12 AB13 AB14 AB15 AB16 AB17 AB18 AB19 AB20 AB21 AB22 AB23 AC1 AC2 AC3 AC4 AC5 AC6 AC7 AC8 AC9 AC10 AC11 AC12 AC13 AC14 AC15 AC16 AC17 AC18 AC19 AC20 AC21 AC22 AC23 B1 B2 B3 B4 B5 B6 B7 B8 B9 B10 B11 B12 B13 B14 B15 B16 B17 B18 B19 B20 B21 B22 B23 C1 C2 C22 C23 D1 D2 D22 D23 E1 E2 E22 E23 F1 F2 F22 F23 G1 G2 G22 G23 H1 H2 H22 H23 J1 J2 J22 J23 K1 K2 K22 K23 L1 L2 L22 L23 M1 M2 M22 M23 N1 N2 N22 N23 P1 P2 P22 P23 R1 R2 R22 R23 T1 T2 T22 T23 U1 U2 U22 U23 V1 V2 V22 V23 W1 W2 W22 W23 Y1 Y2 Y22 Y23; U11 A1 A2 A3 A4 A5 A6 A8 A9 A10 A11 A12 A13 B1 B2 B3 B4 B5 B6 B8 B9 B10 B11 B12 B13 C2 C3 C4 C5 C6 C8 C9 C10 C11 C12 D2 D3 D4 D5 D6 D8 D9 D10 D11 D12 E2 E3 E4 E5 E6 E8 E9 E10 E11 E12 F2 F3 F4 F5 F6 F8 F9 F10 F11 F12 G2 G3 G4 G5 G6 G8 G9 G10 G11 G12 H2 H3 H4 H5 H6 H8 H9 H10 H11 H12 J2 J3 J4 J5 J6 J8 J9 J10 J11 J12 K2 K3 K4 K5 K6 K8 K9 K10 K11 K12 L2 L3 L4 L5 L6 L8 L9 L10 L11 L12 M2 M3 M4 M5 M6 M8 M9 M10 M11 M12 N2 N3 N4 N5 N6 N8 N9 N10 N11 N12 P2 P3 P4 P5 P6 P8 P9 P10 P11 P12 R2 R3 R4 R5 R6 R8 R9 R10 R11 R12 T1 T2 T3 T4 T5 T6 T8 T9 T10 T11 T12 T13 U1 U2 U3 U4 U5 U6 U8 U9 U10 U11 U12 U13; U12 A1 A2 A3 A4 A5 A6 A7 A8 A9 A10 A11 A12 A13 A14 A15 A16 A17 A18 A19 A20 A21 A22 A23 A24 A25 A26 A27 A28 A29 AA1 AA2 AA28 AA29 AB1 AB2 AB28 AB29 AC1 AC2 AC28 AC29 AD1 AD2 AD28 AD29 AE1 AE2 AE28 AE29 AF1 AF2 AF28 AF29 AG1 AG2 AG28 AG29 AH1 AH2 AH3 AH4 AH5 AH6 AH7 AH8 AH9 AH10 AH11 AH12 AH13 AH14 AH15 AH16 AH17 AH18 AH19 AH20 AH21 AH22 AH23 AH24 AH25 AH26 AH27 AH28 AH29 AJ1 AJ2 AJ3 AJ4 AJ5 AJ6 AJ7 AJ8 AJ9 AJ10 AJ11 AJ12 AJ13 AJ14 AJ15 AJ16 AJ17 AJ18 AJ19 AJ20 AJ21 AJ22 AJ23 AJ24 AJ25 AJ26 AJ27 AJ28 AJ29 B1 B2 B3 B4 B5 B6 B7 B8 B9 B10 B11 B12 B13 B14 B15 B16 B17 B18 B19 B20 B21 B22 B23 B24 B25 B26 B27 B28 B29 C1 C2 C28 C29 D1 D2 D28 D29 E1 E2 E28 E29 F1 F2 F28 F29 G1 G2 G28 G29 H1 H2 H28 H29 J1 J2 J28 J29 K1 K2 K28 K29 L1 L2 L28 L29 M1 M2 M28 M29 N1 N2 N28 N29 P1 P2 P28 P29 R1 R2 R28 R29 T1 T2 T28 T29 U1 U2 U28 U29 V1 V2 V28 V29 W1 W2 W28 W29 Y1 Y2 Y28 Y29; U13 A1 A2 A3 A4 A5 A6 A7 A8 A9 A10 A11 A12 A13 A14 A15 A16 A17 A18 A19 A20 A21 A22 A23 A24 A25 A26 A27 AA1 AA2 AA3 AA25 AA26 AA27 AB1 AB2 AB26 AB27 AC1 AC2 AC3 AC25 AC26 AC27 AD1 AD2 AD26 AD27 AE1 AE2 AE26 AE27 AF1 AF2 AF3 AF4 AF5 AF6 AF7 AF8 AF9 AF10 AF11 AF12 AF13 AF14 AF15 AF16 AF17 AF18 AF19 AF20 AF21 AF22 AF23 AF24 AF25 AF26 AF27 AG1 AG2 AG3 AG4 AG5 AG6 AG7 AG8 AG9 AG10 AG11 AG12 AG13 AG14 AG15 AG16 AG17 AG18 AG19 AG20 AG21 AG22 AG23 AG24 AG25 AG26 AG27 B1 B2 B3 B4 B5 B6 B7 B8 B9 B10 B11 B12 B13 B14 B15 B16 B17 B18 B19 B20 B21 B22 B23 B24 B25 B26 B27 C1 C2 C26 C27 D1 D2 D26 D27 E1 E2 E3 E25 E26 E27 F1 F2 F26 F27 G1 G2 G3 G25 G26 G27 H1 H2 H26 H27 J1 J2 J3 J25 J26 J27 K1 K2 K26 K27 L1 L2 L3 L25 L26 L27 M1 M2 M26 M27 N1 N2 N3 N25 N26 N27 P1 P2 P26 P27 R1 R2 R3 R25 R26 R27 T1 T2 T26 T27 U1 U2 U3 U25 U26 U27 V1 V2 V26 V27 W1 W2 W3 W25 W26 W27 Y1 Y2 Y26 Y27; U14 A1 A2 A3 A7 A8 A9 B1 B2 B3 B7 B8 B9 C1 C2 C3 C7 C8 C9 D1 D2 D3 D7 D8 D9 E1 E2 E3 E7 E8 E9 F1 F2 F3 F7 F8 F9 G1 G2 G3 G7 G8 G9 H1 H2 H3 H7 H8 H9 J1 J2 J3 J7 J8 J9 K1 K2 K3 K7 K8 K9 L1 L2 L3 L7 L8 L9 M1 M2 M3 M7 M8 M9 N1 N2 N3 N7 N8 N9 P1 P2 P3 P7 P8 P9 R1 R2 R3 R7 R8 R9 T1 T2 T3 T7 T8 T9; U15 A4 A6 A9 A11 AA1 AA2 AA3 AA4 AA5 AA6 AA7 AA8 AA9 AA10 AA11 AA12 AA13 AA14 AE1 AE14 AG2 AG13 AH4 AH6 AH9 AH11 B2 B13 D1 D14 H1 H2 H3 H4 H5 H6 H7 H8 H9 H10 H11 H12 H13 H14 J1 J2 J3 J4 J5 J6 J7 J8 J9 J10 J11 J12 J13 J14 K1 K2 K3 K4 K5 K6 K7 K8 K9 K10 K11 K12 K13 K14 L1 L2 L3 L4 L12 L13 L14 M1 M2 M3 M5 M6 M7 M8 M9 M10 M12 M13 M14 N1 N2 N3 N5 N10 N12 N13 N14 P1 P2 P3 P5 P10 P12 P13 P14 R1 R2 R3 R5 R10 R12 R13 R14 T1 T2 T3 T5 T10 T12 T13 T14 U1 U2 U3 U5 U6 U7 U8 U9 U10 U12 U13 U14 V1 V2 V3 V12 V13 V14 W1 W2 W3 W4 W5 W6 W7 W8 W9 W10 W11 W12 W13 W14 Y1 Y2 Y3 Y4 Y5 Y6 Y7 Y8 Y9 Y10 Y11 Y12 Y13 Y14; U16 1 2 3 4 5 6 7 8 9 10 11 12 13 14 15 16; U17 1 2 3 4 5 6 7 8 9 10 11 12 13 14 15 16 17 18 19 20 21 22 23 24; U18 1 2 3 4 5 6; U19 1 2 3 4 5 6 7 8 9 10 11 12 13 14 15 16 17 18 19 20; U20 1 2 3 4 5 6 7 8 9 10 11 12 13 14 15 16 17 18 19 20 21 22 23 24 25 26 27 28 29 30 31 32 33 34 35 36 37 38 39 40 41 42 43 44 45 46 47 48 49; U21 1 2 3 4 5 6 7 8 9 10 11 12 13 14 15 16 17 18 19 20 21 22 23 24 25 26 27 28 29 30 31 32 33 34 35 36 37 38 39 40 41 42 43 44 45 46 47 48 49 50 51 52 53 54 55 56 57 58 59 60 61 62 63 64 65 66 67 68 69; U22 1 2 3 4 5 6 7 8 9 10 11 12 13 14 15 16 17 18 19 20 21 22 23 24 25 26 27 28 29 30 31 32 33 34 35 36 37 38 39 40 41 42 43 44 45 46 47 48 49 50 51 52 53 54 55 56 57 58 59 60 61 62 63 64 65 66 67 68 69 70 71 72 73 74 75 76 77 78 79 80 81 82 83 84 85 86 87 88 89; U23 1 2 3 4 5 6 7 8 9 10 11 12 13 14 15 16 17 18 19 20 21 22 23 24 25 26 27 28 29 30 31 32 33 34 35 36 37 38 39 40 41 42 43 44 45 46 47 48; U24 1 2 3 4 5 6 7 8 9 10 11 12 13 14 15 16 17 18 19 20 21 22 23 24 25; U25 A1 A2 A3 A4 B1 B2 B3 B4 C1 C2 C3 C4 D1 D2 D3 D4 E1 E2 E3 E4; U26 1 2 3 4 5 6 7 8 9 10 11 12 13 14 15 16 17 18 19 20 21 22 23 24 25 26 27 28 29
